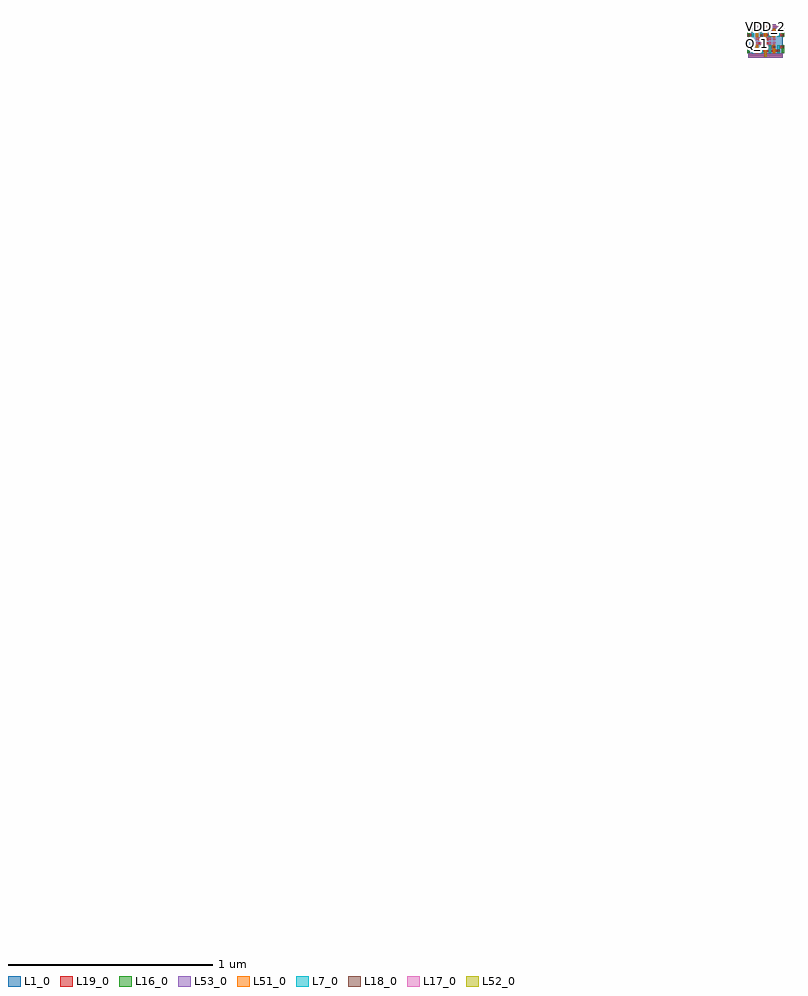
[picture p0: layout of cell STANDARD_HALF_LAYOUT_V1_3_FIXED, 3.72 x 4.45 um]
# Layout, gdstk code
import gdstk
lib = gdstk.Library(unit=1e-6, precision=1e-09)
def R(c, l, rs):  # rectangles x0, y0, x1, y1
    for r in rs: c.add(gdstk.rectangle(r[:2], r[2:], *l))
def A(c, l, x, y, w, h, nx, ny, dx, dy):  # array of equal rectangles
    R(c, l, [(x+i*dx, y+j*dy, x+i*dx+w, y+j*dy+h) for i in range(nx) for j in range(ny)])
def P(c, l, *ps):  # polygons
    for p in ps: c.add(gdstk.Polygon(p, *l))
L1_0 = (1, 0)
L7_0 = (7, 0)
L16_0 = (16, 0)
L17_0 = (17, 0)
L18_0 = (18, 0)
L19_0 = (19, 0)
L51_0 = (51, 0)
L52_0 = (52, 0)
L53_0 = (53, 0)

standard_half_layout_v1_ = lib.new_cell('STANDARD_HALF_LAYOUT_V1_3_FIXED')
A(standard_half_layout_v1_, L1_0, 0, 0, 0.042, 0.072, 4, 2, 0.042, 0.072)
P(standard_half_layout_v1_, L1_0, [(-2.637,-3.867),(-2.637,-3.867),(-2.637,-3.867),(-2.637,-3.867)],
  [(-3.548,-4.293),(-3.548,-4.293),(-3.548,-4.293),(-3.548,-4.293)],
  [(0.151,-0.013),(0.151,-0.013),(0.151,-0.013),(0.151,-0.013)],
  [(0.151,0.157),(0.151,0.157),(0.151,0.157),(0.151,0.157)])
A(standard_half_layout_v1_, L7_0, 0.015, 0.011, 0.012, 0.04, 4, 2, 0.042, 0.082)
R(standard_half_layout_v1_, L16_0, [(0.078,-0.006,0.09,0.051), (-0.006,0.011,0.006,0.051), (0.036,0.011,0.048,0.068), (0.057,0.011,0.069,0.068), (0.099,0.011,0.111,0.068), (0.12,0.011,0.132,0.068), (0.162,0.011,0.174,0.051), (0.036,0.076,0.048,0.133), (0.057,0.076,0.069,0.133), (0.099,0.076,0.111,0.133), (0.12,0.076,0.132,0.133), (-0.006,0.093,0.006,0.133), (0.078,0.093,0.09,0.15), (0.162,0.093,0.174,0.133)])
R(standard_half_layout_v1_, L17_0, [(0.036,0.056,0.048,0.068), (0.057,0.056,0.069,0.068), (0.099,0.056,0.111,0.068), (0.12,0.056,0.132,0.068), (0.036,0.076,0.048,0.088), (0.057,0.076,0.069,0.088), (0.099,0.076,0.111,0.088), (0.12,0.076,0.132,0.088)])
A(standard_half_layout_v1_, L18_0, -0.005, 0.038, 0.01, 0.01, 3, 2, 0.063, 0.058)
R(standard_half_layout_v1_, L18_0, [(0.079,-0.005,0.089,0.005), (0.016,0.02,0.026,0.03), (0.142,0.02,0.152,0.03), (0.163,0.038,0.173,0.048), (0.037,0.057,0.047,0.067), (0.1,0.057,0.11,0.067), (0.037,0.077,0.047,0.087), (0.1,0.077,0.11,0.087), (0.163,0.096,0.173,0.106), (0.016,0.114,0.026,0.124), (0.142,0.114,0.152,0.124), (0.079,0.139,0.089,0.149)])
R(standard_half_layout_v1_, L19_0, [(0,-0.011,0.168,0.011), (0.015,0.02,0.153,0.03), (-0.006,0.037,0.016,0.049), (0.057,0.037,0.132,0.049), (0.151,0.037,0.174,0.049), (0.036,0.057,0.111,0.067), (0.036,0.077,0.111,0.087), (-0.006,0.095,0.016,0.107), (0.057,0.095,0.132,0.107), (0.151,0.095,0.174,0.107), (0.015,0.114,0.153,0.124), (0,0.133,0.168,0.155)])
R(standard_half_layout_v1_, L51_0, [(0.078,-0.006,0.09,0.051), (0.036,0.011,0.048,0.068), (0.057,0.011,0.069,0.068), (0.099,0.011,0.111,0.068), (0.12,0.011,0.132,0.068), (0.036,0.076,0.048,0.133), (0.057,0.076,0.069,0.133), (0.099,0.076,0.111,0.133), (0.12,0.076,0.132,0.133), (0.078,0.093,0.09,0.15)])
R(standard_half_layout_v1_, L52_0, [(0.079,-0.005,0.089,0.005), (0.079,0.139,0.089,0.149)])
R(standard_half_layout_v1_, L53_0, [(0,-0.011,0.168,0.011), (0,0.133,0.168,0.155)])
standard_half_layout_v1_.add(gdstk.Label('Q_1', (0.042,0.062), layer=17, texttype=0))
standard_half_layout_v1_.add(gdstk.Label('QB_1', (0.105,0.062), layer=17, texttype=0))
standard_half_layout_v1_.add(gdstk.Label('Q_2', (0.126,0.062), layer=17, texttype=0))
standard_half_layout_v1_.add(gdstk.Label('WL_1', (0.084,0.025), layer=19, texttype=0))
standard_half_layout_v1_.add(gdstk.Label('VSS_1', (0.081,0), layer=19, texttype=0))
standard_half_layout_v1_.add(gdstk.Label('BLB_1', (0.162,0.043), layer=19, texttype=0))
standard_half_layout_v1_.add(gdstk.Label('BL_1', (0.005,0.043), layer=19, texttype=0))
standard_half_layout_v1_.add(gdstk.Label('WLB_1', (0.084,0.119), layer=19, texttype=0))
standard_half_layout_v1_.add(gdstk.Label('VDD_1', (0.081,0), layer=53, texttype=0))
standard_half_layout_v1_.add(gdstk.Label('VDD_2', (0.081,0.144), layer=53, texttype=0))

lib.write_gds('STANDARD_HALF_LAYOUT_V1_3_FIXED.gds')
